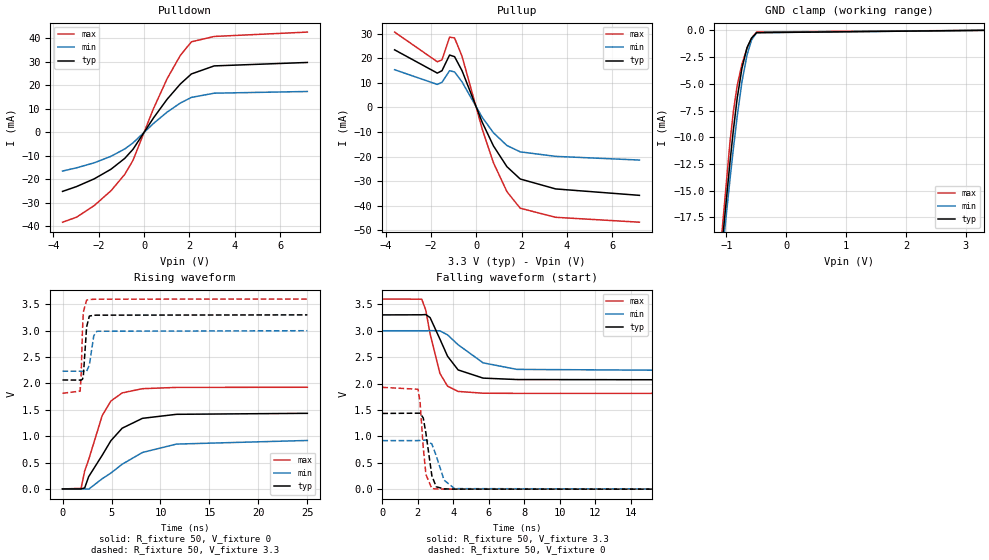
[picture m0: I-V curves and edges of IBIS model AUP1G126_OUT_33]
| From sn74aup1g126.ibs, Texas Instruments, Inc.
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[Model]   AUP1G126_OUT_33
Model_type  3-state
Enable   Active-High
Vref =   0
Rref =   1E6
Cref =   30p
Vmeas =   1.65
| variable   typ   min   max
C_comp   2.07pF   1.81pF   2.41pF
| C_pullup   3.15pF   1.95pF   4.02pF
| C_pulldown   2.43pF   2.24pF   2.96pF
| C_tri-state   2.07pF   1.81pF   2.41pF
[Temperature Range]   40   100   -40
| Ambient temperature   25   85   -40
[Voltage range]   3.3   3   3.6
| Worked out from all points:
|   slope of the pulldown table from 0 to 0.495 V, typ, clamps not added: 68.4 ohm
|   slope of the pullup table from 0 to 0.495 V, typ, clamps not added: 45.7 ohm
|   GND clamp passes 1 mA (typ) near -0.61 V on its own axis
|   rising waveform, R_fixture 50, V_fixture 0: 20-80 % time 3.2ns typ, 4.84ns min, 2.12ns max; typ from 0 V to 1.43 V
|   falling waveform, R_fixture 50, V_fixture 3.3: 20-80 % time 1.09ns typ, 1.78ns min, 732ps max; typ from 3.3 V to 2.07 V
|   rising waveform, R_fixture 50, V_fixture 3.3: 20-80 % time 238ps typ, 345ps min, 188ps max; typ from 2.07 V to 3.3 V
|   falling waveform, R_fixture 50, V_fixture 0: 20-80 % time 349ps typ, 519ps min, 263ps max; typ from 1.43 V to 0 V
[GND Clamp]
| AUP1G126_OUT_33
|   Voltage   I(typ)   I(min)   I(max)
-3.6V     -193.5mA   -179.8mA   -210.3mA
-1.125V   -23.21mA   -23.99mA   -22.31mA
-1.1V     -21.68mA   -22.59mA   -20.6mA
-1.075V   -20.16mA   -21.2mA    -18.91mA
-940mV    -12.31mA   -13.93mA   -10.42mA
-885mV    -9.392mA   -11.14mA   -7.651mA
-820mV    -6.352mA   -8.056mA   -5.152mA
-740mV    -3.533mA   -4.797mA   -3.135mA
-655mV    -1.602mA   -2.3mA     -1.69mA
-580mV    -733.4uA   -905.1uA   -734uA
-495mV    -220.6uA   -215.1uA   -155.7uA
3.3V      272.6pA    1.916nA    65.76pA
[Pulldown]
| AUP1G126_OUT_33
|   Voltage   I(typ)   I(min)   I(max)
-3.6V     -25.22mA   -16.54mA   -38.34mA
-2.985V   -23.17mA   -15.19mA   -36.23mA
-2.205V   -19.89mA   -13.04mA   -31.29mA
-1.46V    -15.76mA   -10.26mA   -24.93mA
-855mV    -11.15mA   -7.128mA   -17.97mA
-490mV    -7.269mA   -4.538mA   -11.95mA
415mV     6.109mA    3.748mA    10.09mA
1.015V    14.06mA    8.579mA    22.82mA
1.6V      20.58mA    12.45mA    32.78mA
2.085V    24.83mA    14.83mA    38.52mA
3.09V     28.26mA    16.63mA    40.81mA
7.2V      29.73mA    17.36mA    42.67mA
[Pullup]
| AUP1G126_OUT_33
|   Voltage   I(typ)   I(min)   I(max)
-3.6V     23.4mA     15.31mA    30.62mA
-1.715V   13.93mA    9.327mA    18.54mA
-1.51V    14.91mA    10.2mA     19.34mA
-1.175V   21.28mA    14.91mA    28.58mA
-955mV    20.62mA    14.4mA     28.23mA
-625mV    14.91mA    10.34mA    20.78mA
270mV     -6.183mA   -4.136mA   -9mA
765mV     -15.76mA   -10.39mA   -22.64mA
1.355V    -24.14mA   -15.52mA   -34.29mA
1.94V     -29.14mA   -18.1mA    -41.04mA
3.505V    -33.19mA   -19.94mA   -44.73mA
7.2V      -35.8mA    -21.44mA   -46.72mA
[Ramp]
| AUP1G126_OUT_33
| variable   typ   min   max
dV/dt_r   0.86/3.21E-09   0.55/4.86E-09   1.16/2.12E-09
dV/dt_f   0.74/1.10E-09   0.46/1.78E-09   1.08/7.37E-10
R_load = 50
[Rising Waveform]
| AUP1G126_OUT_33
R_fixture =   50
C_fixture =   0
L_fixture =   0
V_fixture =   0
V_fixture_min = 0
V_fixture_max = 0
|   Time   V(typ)   V(min)   V(max)
0s        12.11nV    31.97nV    1.283nV
1.895ns   449.3uV    104.7uV    11.78mV
2.265ns   20.71mV    496.4uV    341.8mV
2.67ns    233.6mV    -3.926mV   557.4mV
4.045ns   637.1mV    192.9mV    1.388V
4.94ns    915.4mV    301.7mV    1.668V
6.09ns    1.152V     469.4mV    1.821V
8.16ns    1.339V     691.7mV    1.901V
11.62ns   1.415V     850.6mV    1.925V
24.99ns   1.434V     919.3mV    1.928V
[Falling Waveform]
| AUP1G126_OUT_33
R_fixture =   50
C_fixture =   0
L_fixture =   0
V_fixture =   3.3
V_fixture_min = 3
V_fixture_max = 3.6
|   Time   V(typ)   V(min)   V(max)
0s        3.3V       3V         3.6V
2.22ns    3.302V     3V         3.598V
2.445ns   3.307V     2.999V     3.393V
2.69ns    3.249V     3.002V     2.943V
3.245ns   2.842V     2.998V     2.19V
3.675ns   2.517V     2.922V     1.95V
4.27ns    2.258V     2.735V     1.851V
5.68ns    2.103V     2.392V     1.817V
7.59ns    2.076V     2.268V     1.814V
24.99ns   2.067V     2.234V     1.814V
[Rising Waveform]
| AUP1G126_OUT_33
R_fixture =   50
C_fixture =   0
L_fixture =   0
V_fixture =   3.3
V_fixture_min = 3
V_fixture_max = 3.6
|   Time   V(typ)   V(min)   V(max)
0s        2.066V     2.232V     1.814V
1.795ns   2.064V     2.232V     1.854V
1.895ns   2.063V     2.232V     2.139V
2.04ns    2.081V     2.231V     3.02V
2.125ns   2.14V      2.23V      3.355V
2.46ns    3.074V     2.232V     3.58V
2.74ns    3.277V     2.347V     3.591V
3.19ns    3.293V     2.904V     3.596V
3.515ns   3.295V     2.99V      3.598V
24.99ns   3.3V       3V         3.6V
[Falling Waveform]
| AUP1G126_OUT_33
R_fixture =   50
C_fixture =   0
L_fixture =   0
V_fixture =   0
V_fixture_min = 0
V_fixture_max = 0
|   Time   V(typ)   V(min)   V(max)
0s        1.434V     920.1mV    1.928V
2.01ns    1.439V     920.3mV    1.892V
2.125ns   1.438V     921.9mV    1.647V
2.305ns   1.349V     926.4mV    791mV
2.455ns   1.059V     929.6mV    278.5mV
2.79ns    254.7mV    855mV      11.12mV
3.035ns   45.54mV    633.7mV    4.265mV
3.48ns    4.888mV    169.9mV    1.302mV
4.075ns   1.246mV    10.01mV    302uV
24.99ns   26.83nV    71.48nV    5.451nV
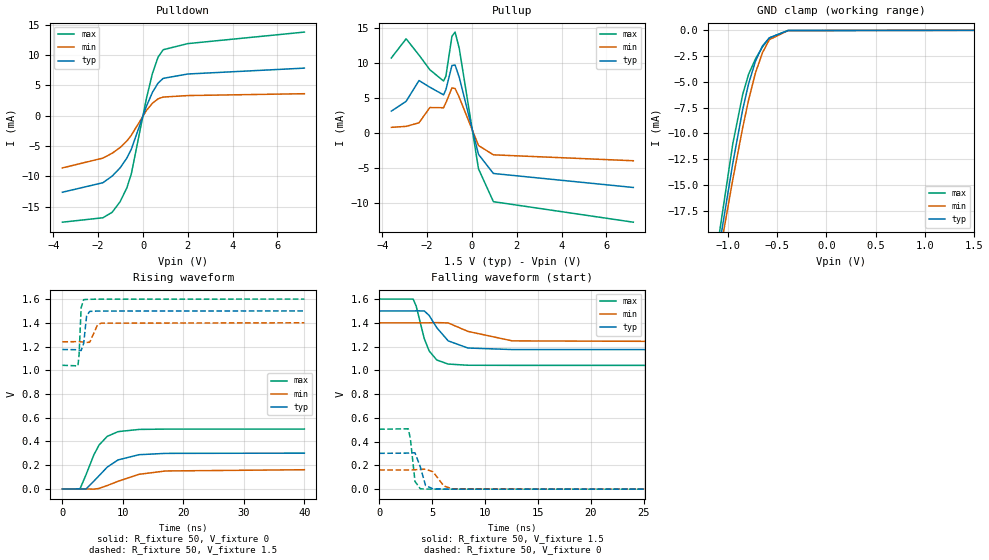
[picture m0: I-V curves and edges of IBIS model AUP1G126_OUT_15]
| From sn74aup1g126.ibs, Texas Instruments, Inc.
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[Model]   AUP1G126_OUT_15
Model_type  3-state
Enable   Active-High
Vref =   0
Rref =   1E6
Cref =   30p
Vmeas =   0.75
| variable   typ   min   max
C_comp   2.22pF   2.00pF   2.44pF
| C_pullup   3.10pF   2.13pF   3.96pF
| C_pulldown   2.66pF   2.26pF   3.14pF
| C_tri-state   2.22pF   2.00pF   2.44pF
[Temperature Range]   40   100   -40
| Ambient temperature   25   85   -40
[Voltage range]   1.5   1.4   1.6
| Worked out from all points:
|   slope of the pulldown table from 0 to 0.225 V, typ, clamps not added: 101 ohm
|   slope of the pullup table from 0 to 0.225 V, typ, clamps not added: 90.3 ohm
|   GND clamp passes 1 mA (typ) near -0.61 V on its own axis
|   rising waveform, R_fixture 50, V_fixture 0: 20-80 % time 4ns typ, 5.61ns min, 2.86ns max; typ from 0 V to 0.302 V
|   falling waveform, R_fixture 50, V_fixture 1.5: 20-80 % time 1.73ns typ, 2.75ns min, 1.14ns max; typ from 1.5 V to 1.18 V
|   rising waveform, R_fixture 50, V_fixture 1.5: 20-80 % time 384ps typ, 610ps min, 264ps max; typ from 1.18 V to 1.5 V
|   falling waveform, R_fixture 50, V_fixture 0: 20-80 % time 497ps typ, 780ps min, 340ps max; typ from 0.302 V to 0 V
[GND Clamp]
| AUP1G126_OUT_15
|   Voltage   I(typ)   I(min)   I(max)
-3.6V     -193.5mA   -179.8mA   -210.3mA
-1.13V    -23.52mA   -24.27mA   -22.66mA
-1.105V   -21.99mA   -22.87mA   -20.94mA
-1.085V   -20.77mA   -21.75mA   -19.58mA
-950mV    -12.87mA   -14.45mA   -10.98mA
-850mV    -7.684mA   -9.444mA   -6.215mA
-790mV    -5.171mA   -6.747mA   -4.259mA
-720mV    -2.982mA   -4.115mA   -2.762mA
-650mV    -1.524mA   -2.184mA   -1.616mA
-580mV    -733.4uA   -905.1uA   -734uA
-390mV    -21.99uA   -24.7uA    -8.299uA
1.5V      145.1pA    3.388nA    27.28pA
[Pulldown]
| AUP1G126_OUT_15
|   Voltage   I(typ)   I(min)   I(max)
-3.6V     -12.64mA   -8.632mA   -17.58mA
-1.79V    -11.07mA   -7.008mA   -16.85mA
-1.38V    -9.983mA   -6.211mA   -15.95mA
-1.025V   -8.629mA   -5.274mA   -14.21mA
-725mV    -7.022mA   -4.203mA   -11.94mA
-525mV    -5.567mA   -3.253mA   -9.657mA
150mV     1.53mA     832.4uA    2.806mA
420mV     3.835mA    2.043mA    6.955mA
670mV     5.357mA    2.767mA    9.628mA
900mV     6.139mA    3.055mA    10.86mA
1.995V    6.857mA    3.303mA    11.87mA
7.2V      7.827mA    3.609mA    13.77mA
[Pullup]
| AUP1G126_OUT_15
|   Voltage   I(typ)   I(min)   I(max)
-3.6V     3.098mA    783.1uA    10.69mA
-2.94V    4.495mA    918.5uA    13.42mA
-2.365V   7.463mA    1.433mA    11.1mA
-1.88V    6.507mA    3.61mA     9.001mA
-1.27V    5.419mA    3.581mA    7.399mA
-1.165V   6.162mA    4.294mA    8.081mA
-895mV    9.612mA    6.412mA    13.79mA
-755mV    9.683mA    6.329mA    14.38mA
-570mV    7.923mA    5.076mA    12.08mA
290mV     -3.075mA   -1.814mA   -5.141mA
955mV     -5.807mA   -3.143mA   -9.829mA
7.2V      -7.803mA   -3.988mA   -12.76mA
[Ramp]
| AUP1G126_OUT_15
| variable   typ   min   max
dV/dt_r   0.18/4.04E-09   0.10/5.70E-09   0.30/2.88E-09
dV/dt_f   0.20/1.74E-09   0.10/2.77E-09   0.34/1.15E-09
R_load = 50
[Rising Waveform]
| AUP1G126_OUT_15
R_fixture =   50
C_fixture =   0
L_fixture =   0
V_fixture =   0
V_fixture_min = 0
V_fixture_max = 0
|   Time   V(typ)   V(min)   V(max)
0s        6.328nV    24.54nV    515.8pV
2.895ns   176.2uV    91.32uV    -1.518mV
3.905ns   -804.2uV   121.2uV    119.1mV
5.215ns   66.08mV    -2.019mV   288.5mV
6.065ns   111.2mV    4.049mV    370mV
7.41ns    183.6mV    28.66mV    442.7mV
9.205ns   244.6mV    64.45mV    482.7mV
12.69ns   288.5mV    123.6mV    501.5mV
17.03ns   299.6mV    151.4mV    504.1mV
40ns      301.6mV    161.8mV    504.4mV
[Falling Waveform]
| AUP1G126_OUT_15
R_fixture =   50
C_fixture =   0
L_fixture =   0
V_fixture =   1.5
V_fixture_min = 1.4
V_fixture_max = 1.6
|   Time   V(typ)   V(min)   V(max)
0s        1.5V       1.4V       1.6V
3.205ns   1.5V       1.4V       1.6V
3.495ns   1.501V     1.4V       1.54V
4.255ns   1.5V       1.4V       1.267V
4.72ns    1.462V     1.4V       1.163V
5.44ns    1.359V     1.402V     1.087V
6.52ns    1.248V     1.399V     1.053V
8.38ns    1.188V     1.328V     1.043V
12.58ns   1.175V     1.248V     1.042V
40ns      1.175V     1.24V      1.042V
[Rising Waveform]
| AUP1G126_OUT_15
R_fixture =   50
C_fixture =   0
L_fixture =   0
V_fixture =   1.5
V_fixture_min = 1.4
V_fixture_max = 1.6
|   Time   V(typ)   V(min)   V(max)
0s        1.175V     1.24V      1.042V
2.575ns   1.173V     1.241V     1.037V
2.76ns    1.17V      1.241V     1.13V
3.1ns     1.166V     1.24V      1.527V
3.515ns   1.225V     1.237V     1.595V
4.01ns    1.459V     1.235V     1.597V
4.52ns    1.496V     1.236V     1.598V
5.815ns   1.499V     1.383V     1.599V
6.4ns     1.499V     1.397V     1.599V
40ns      1.5V       1.4V       1.6V
[Falling Waveform]
| AUP1G126_OUT_15
R_fixture =   50
C_fixture =   0
L_fixture =   0
V_fixture =   0
V_fixture_min = 0
V_fixture_max = 0
|   Time   V(typ)   V(min)   V(max)
0s        301.6mV    161.8mV    504.4mV
2.74ns    303.5mV    161.4mV    508.3mV
2.94ns    306.8mV    161.5mV    427.1mV
3.38ns    305.5mV    163.2mV    65mV
3.885ns   187.3mV    166.3mV    3.409mV
4.375ns   31.32mV    168.3mV    980.1uV
5.08ns    2.591mV    146.3mV    226.7uV
6.115ns   526.7uV    26.51mV    40.87uV
6.9ns     204.5uV    3.034mV    12.93uV
40ns      31.36nV    49.94nV    8.258nV
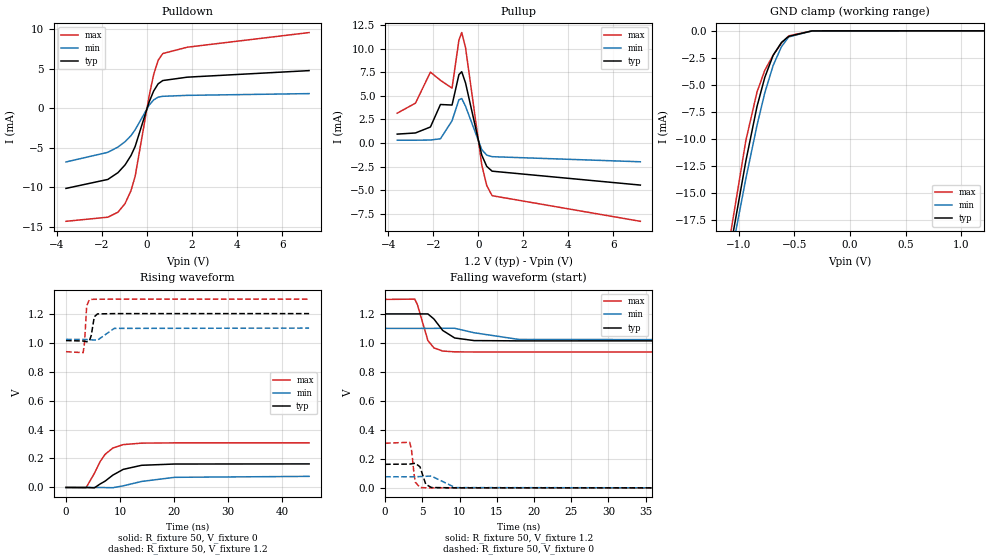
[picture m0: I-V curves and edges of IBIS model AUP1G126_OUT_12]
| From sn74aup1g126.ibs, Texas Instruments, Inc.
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[Model]   AUP1G126_OUT_12
Model_type  3-state
Enable   Active-High
Vref =   0
Rref =   1E6
Cref =   30p
Vmeas =   0.6
| variable   typ   min   max
C_comp   2.26pF   2.06pF   2.47pF
| C_pullup   3.02pF   2.17pF   3.84pF
| C_pulldown   2.70pF   2.26pF   3.18pF
| C_tri-state   2.26pF   2.06pF   2.47pF
[Temperature Range]   40   100   -40
| Ambient temperature   25   85   -40
[Voltage range]   1.2   1.1   1.3
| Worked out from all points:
|   slope of the pulldown table from 0 to 0.18 V, typ, clamps not added: 125 ohm
|   slope of the pullup table from 0 to 0.18 V, typ, clamps not added: 123 ohm
|   GND clamp passes 1 mA (typ) near -0.61 V on its own axis
|   rising waveform, R_fixture 50, V_fixture 0: 20-80 % time 4.19ns typ, 5.98ns min, 3ns max; typ from 0 V to 0.163 V
|   falling waveform, R_fixture 50, V_fixture 1.2: 20-80 % time 2.02ns typ, 3.4ns min, 1.28ns max; typ from 1.2 V to 1.01 V
|   rising waveform, R_fixture 50, V_fixture 1.2: 20-80 % time 457ps typ, 759ps min, 311ps max; typ from 1.01 V to 1.2 V
|   falling waveform, R_fixture 50, V_fixture 0: 20-80 % time 588ps typ, 991ps min, 389ps max; typ from 0.163 V to 0 V
[GND Clamp]
| AUP1G126_OUT_12
|   Voltage   I(typ)   I(min)   I(max)
-3.6V     -193.5mA   -179.8mA   -210.3mA
-1.12V    -22.91mA   -23.71mA   -21.97mA
-1.1V     -21.68mA   -22.59mA   -20.6mA
-1.08V    -20.47mA   -21.48mA   -19.25mA
-935mV    -12.04mA   -13.67mA   -10.14mA
-835mV    -7.001mA   -8.742mA   -5.664mA
-765mV    -4.304mA   -5.731mA   -3.651mA
-690mV    -2.262mA   -3.204mA   -2.243mA
-615mV    -1.069mA   -1.463mA   -1.136mA
-550mV    -509.1uA   -564.4uA   -463.6uA
-340mV    -5.773uA   -7.67uA    -1.491uA
1.2V      128.1pA    3.167nA    21.35pA
[Pulldown]
| AUP1G126_OUT_12
|   Voltage   I(typ)   I(min)   I(max)
-3.6V     -10.14mA   -6.792mA   -14.3mA
-1.74V    -9.004mA   -5.576mA   -13.78mA
-1.29V    -8.143mA   -4.904mA   -13.15mA
-975mV    -7.165mA   -4.229mA   -12.05mA
-710mV    -5.969mA   -3.453mA   -10.41mA
-525mV    -4.815mA   -2.713mA   -8.581mA
90mV      761.5uA    381.6uA    1.487mA
295mV     2.185mA    1.055mA    4.264mA
495mV     3.092mA    1.407mA    6.07mA
700mV     3.505mA    1.511mA    6.919mA
1.785V    3.931mA    1.63mA     7.723mA
7.2V      4.761mA    1.852mA    9.574mA
[Pullup]
| AUP1G126_OUT_12
|   Voltage   I(typ)   I(min)   I(max)
-3.6V     938.3uA    292.3uA    3.161mA
-2.79V    1.061mA    291.5uA    4.222mA
-2.125V   1.693mA    310.3uA    7.513mA
-1.68V    4.08mA     442.8uA    6.642mA
-1.165V   4.022mA    2.354mA    5.813mA
-860mV    7.245mA    4.579mA    10.91mA
-735mV    7.558mA    4.716mA    11.71mA
-565mV    6.361mA    3.892mA    10.1mA
155mV     -1.288mA   -703.8uA   -2.322mA
375mV     -2.48mA    -1.288mA   -4.509mA
615mV     -2.993mA   -1.455mA   -5.593mA
7.2V      -4.468mA   -1.996mA   -8.31mA
[Ramp]
| AUP1G126_OUT_12
| variable   typ   min   max
dV/dt_r   0.10/4.27E-09   0.046/6.13E-09   0.19/3.03E-09
dV/dt_f   0.11/2.03E-09   0.047/3.43E-09   0.22/1.29E-09
R_load = 50
[Rising Waveform]
| AUP1G126_OUT_12
R_fixture =   50
C_fixture =   0
L_fixture =   0
V_fixture =   0
V_fixture_min = 0
V_fixture_max = 0
|   Time   V(typ)   V(min)   V(max)
0s        5.831nV    23.96nV    441.9pV
3.715ns   83.54uV    62.88uV    -2.432mV
5.255ns   -2.69mV    64uV       97.35mV
6.32ns    24.19mV    -10.45uV   178.6mV
7.235ns   43.53mV    -726.6uV   228.5mV
8.675ns   85.25mV    -1.647mV   272.2mV
10.59ns   124.8mV    11.2mV     295.8mV
14ns      153.1mV    41.61mV    306.1mV
20.09ns   161.8mV    70.01mV    307.8mV
45ns      162.6mV    76.67mV    307.8mV
[Falling Waveform]
| AUP1G126_OUT_12
R_fixture =   50
C_fixture =   0
L_fixture =   0
V_fixture =   1.2
V_fixture_min = 1.1
V_fixture_max = 1.3
|   Time   V(typ)   V(min)   V(max)
0s        1.2V       1.1V       1.3V
3.985ns   1.2V       1.1V       1.302V
4.33ns    1.2V       1.1V       1.266V
5.75ns    1.2V       1.1V       1.016V
6.56ns    1.165V     1.1V       965.8mV
7.74ns    1.086V     1.101V     943.8mV
9.35ns    1.034V     1.101V     938.2mV
11.96ns   1.016V     1.07V      937.4mV
17.96ns   1.014V     1.024V     937.4mV
45ns      1.014V     1.022V     937.4mV
[Rising Waveform]
| AUP1G126_OUT_12
R_fixture =   50
C_fixture =   0
L_fixture =   0
V_fixture =   1.2
V_fixture_min = 1.1
V_fixture_max = 1.3
|   Time   V(typ)   V(min)   V(max)
0s        1.014V     1.022V     937.3mV
3.175ns   1.011V     1.022V     930.4mV
3.435ns   1.009V     1.022V     997.6mV
3.83ns    1.006V     1.021V     1.252V
4.32ns    1.011V     1.02V      1.296V
4.675ns   1.049V     1.019V     1.298V
5.24ns    1.178V     1.018V     1.299V
5.835ns   1.198V     1.017V     1.299V
8.93ns    1.2V       1.098V     1.3V
45ns      1.2V       1.1V       1.3V
[Falling Waveform]
| AUP1G126_OUT_12
R_fixture =   50
C_fixture =   0
L_fixture =   0
V_fixture =   0
V_fixture_min = 0
V_fixture_max = 0
|   Time   V(typ)   V(min)   V(max)
0s        162.6mV    76.67mV    307.8mV
3.3ns     163.9mV    76.37mV    314.5mV
3.54ns    165.7mV    76.37mV    267.6mV
3.885ns   168.5mV    76.58mV    98.52mV
4.065ns   169.6mV    76.82mV    39.45mV
4.685ns   145.5mV    78.05mV    2.414mV
5.465ns   24.6mV     79.87mV    463uV
6.22ns    2.478mV    81.32mV    131.2uV
9.425ns   84.4uV     1.797mV    1.763uV
45ns      38.99nV    75.01nV    13.93nV
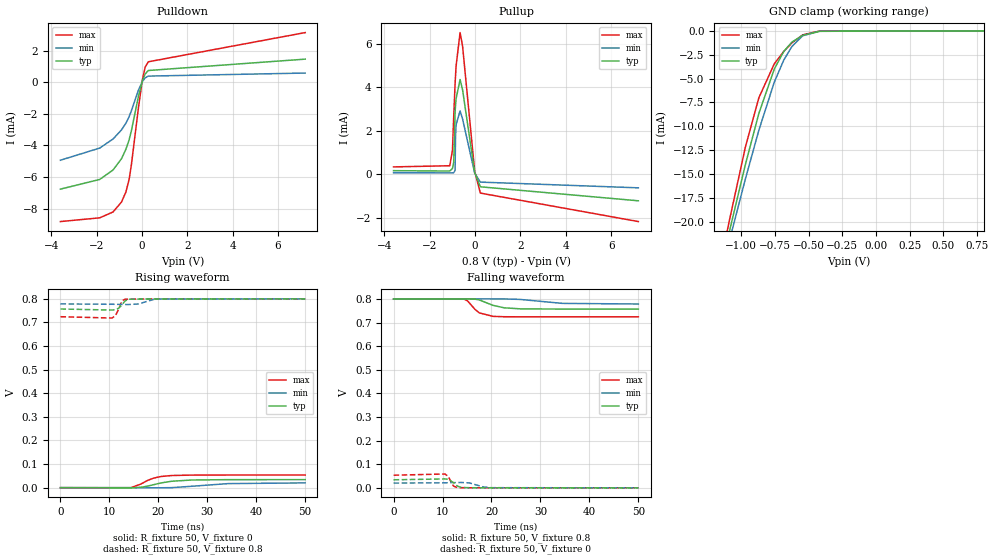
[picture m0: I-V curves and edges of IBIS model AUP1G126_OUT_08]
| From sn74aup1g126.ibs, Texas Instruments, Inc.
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[Model]   AUP1G126_OUT_08
Model_type  3-state
Enable   Active-High
Vref =   0
Rref =   1E6
Cref =   30p
Vmeas =   0.4
| variable   typ   min   max
C_comp   2.32pF   2.11pF   2.51pF
| C_pullup   2.79pF   2.25pF   3.33pF
| C_pulldown   2.67pF   2.23pF   3.12pF
| C_tri-state   2.32pF   2.11pF   2.51pF
[Temperature Range]   40   100   -40
| Ambient temperature   25   85   -40
[Voltage range]   0.8   0.8   0.8
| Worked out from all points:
|   slope of the pulldown table from 0 to 0.12 V, typ, clamps not added: 257 ohm
|   slope of the pullup table from 0 to 0.12 V, typ, clamps not added: 302 ohm
|   GND clamp passes 1 mA (typ) near -0.61 V on its own axis
[GND Clamp]
| AUP1G126_OUT_08
|   Voltage   I(typ)   I(min)   I(max)
-3.6V     -193.5mA   -179.8mA   -210.3mA
-1.13V    -23.52mA   -24.27mA   -22.66mA
-1.11V    -22.29mA   -23.15mA   -21.28mA
-1.09V    -21.07mA   -22.03mA   -19.92mA
-970mV    -13.99mA   -15.5mA    -12.16mA
-870mV    -8.642mA   -10.4mA    -7.008mA
-755mV    -3.985mA   -5.347mA   -3.436mA
-685mV    -2.156mA   -3.064mA   -2.16mA
-625mV    -1.184mA   -1.653mA   -1.265mA
-545mV    -476.4uA   -519.4uA   -425.6uA
-420mV    -46.16uA   -47.99uA   -21.13uA
800mV     106.6pA    549.6pA    15.87pA
[Pulldown]
| AUP1G126_OUT_08
|   Voltage   I(typ)   I(min)   I(max)
-3.6V     -6.763mA   -4.935mA   -8.814mA
-1.865V   -6.15mA    -4.166mA   -8.578mA
-1.28V    -5.555mA   -3.595mA   -8.209mA
-905mV    -4.84mA    -3.018mA   -7.581mA
-710mV    -4.24mA    -2.594mA   -6.943mA
-570mV    -3.655mA   -2.186mA   -6.156mA
-470mV    -3.08mA    -1.812mA   -5.243mA
-155mV    -882uA     -491.6uA   -1.594mA
15mV      70.31uA    36.95uA    134.1uA
140mV     523.3uA    274.6uA    953.9uA
280mV     740uA      385.5uA    1.291mA
7.2V      1.459mA    578.6uA    3.138mA
[Pullup]
| AUP1G126_OUT_08
|   Voltage   I(typ)   I(min)   I(max)
-3.6V     173.2uA    77.31uA    346.4uA
-1.12V    155.8uA    71.47uA    400.2uA
-1V       271.5uA    72.31uA    1.109mA
-945mV    558.4uA    80.56uA    2.665mA
-885mV    2.856mA    183.3uA    4.162mA
-865mV    3.17mA     1.755mA    4.547mA
-840mV    3.485mA    2.289mA    4.99mA
-665mV    4.366mA    2.921mA    6.526mA
-555mV    3.897mA    2.556mA    5.908mA
-20mV     90.78uA    56.3uA     147uA
230mV     -568.5uA   -352.9uA   -857.8uA
7.2V      -1.213mA   -616.6uA   -2.168mA
[Ramp]
| AUP1G126_OUT_08
| variable   typ   min   max
dV/dt_r   0.02/4.96E-09   0.012/7.32E-09   0.032/3.51E-09
dV/dt_f   0.026/3.55E-09   0.013/5.92E-09   0.045/2.22E-09
R_load = 50
[Rising Waveform]
| AUP1G126_OUT_08
R_fixture =   50
C_fixture =   0
L_fixture =   0
V_fixture =   0
V_fixture_min = 0
V_fixture_max = 0
|   Time   V(typ)   V(min)   V(max)
0s        5.542nV    24.01nV    351.9pV
14.39ns   -800.9uV   -6.753uV   -177.1uV
16.41ns   1.408mV    -201.9uV   15.15mV
17.87ns   6.741mV    -525.9uV   31.3mV
19.04ns   12.57mV    -700.1uV   40.49mV
20.63ns   20.31mV    -474.3uV   47.54mV
22.7ns    27.09mV    4.572uV    51.42mV
26.76ns   32.41mV    5.761mV    53.25mV
34.21ns   33.95mV    17.14mV    53.49mV
50ns      34.06mV    20.22mV    53.5mV
[Falling Waveform]
| AUP1G126_OUT_08
R_fixture =   50
C_fixture =   0
L_fixture =   0
V_fixture =   0.8
V_fixture_min = 0.8
V_fixture_max = 0.8
|   Time   V(typ)   V(min)   V(max)
0s        800mV      800mV      800mV
14.38ns   800.4mV    800mV      799.3mV
15.14ns   800.3mV    800mV      791.4mV
16.62ns   799.3mV    800.2mV    756.1mV
17.52ns   795.8mV    800.3mV    741mV
20.3ns    773mV      800.3mV    726.3mV
22.6ns    762.5mV    800.1mV    724.7mV
25.84ns   758.2mV    798.1mV    724.4mV
34.46ns   757.1mV    781.3mV    724.4mV
50ns      757.1mV    778.6mV    724.4mV
[Rising Waveform]
| AUP1G126_OUT_08
R_fixture =   50
C_fixture =   0
L_fixture =   0
V_fixture =   0.8
V_fixture_min = 0.8
V_fixture_max = 0.8
|   Time   V(typ)   V(min)   V(max)
0s        757.1mV    778.6mV    724.4mV
10.55ns   752.6mV    777.2mV    718.7mV
11.26ns   754.2mV    776.9mV    729.2mV
11.87ns   760mV      776.7mV    754.8mV
12.57ns   774.5mV    776.4mV    791mV
13.19ns   790.5mV    776.1mV    798.6mV
13.83ns   798.5mV    775.9mV    798.9mV
15.9ns    799.3mV    778.4mV    799.4mV
19.34ns   799.7mV    799.3mV    799.9mV
50ns      800mV      800mV      800mV
[Falling Waveform]
| AUP1G126_OUT_08
R_fixture =   50
C_fixture =   0
L_fixture =   0
V_fixture =   0
V_fixture_min = 0
V_fixture_max = 0
|   Time   V(typ)   V(min)   V(max)
0s        34.06mV    20.29mV    53.5mV
10.49ns   37.78mV    21.23mV    58.72mV
11.16ns   36.36mV    21.5mV     48.55mV
12.25ns   22.02mV    21.99mV    7.433mV
13ns      8.183mV    22.4mV     1.441mV
13.77ns   1.694mV    22.76mV    851.3uV
15.48ns   552.1uV    20.97mV    343.4uV
18.26ns   260.1uV    4.084mV    38.09uV
19.65ns   144.1uV    754.2uV    12.45uV
50ns      50.89nV    334.7nV    20.45nV
